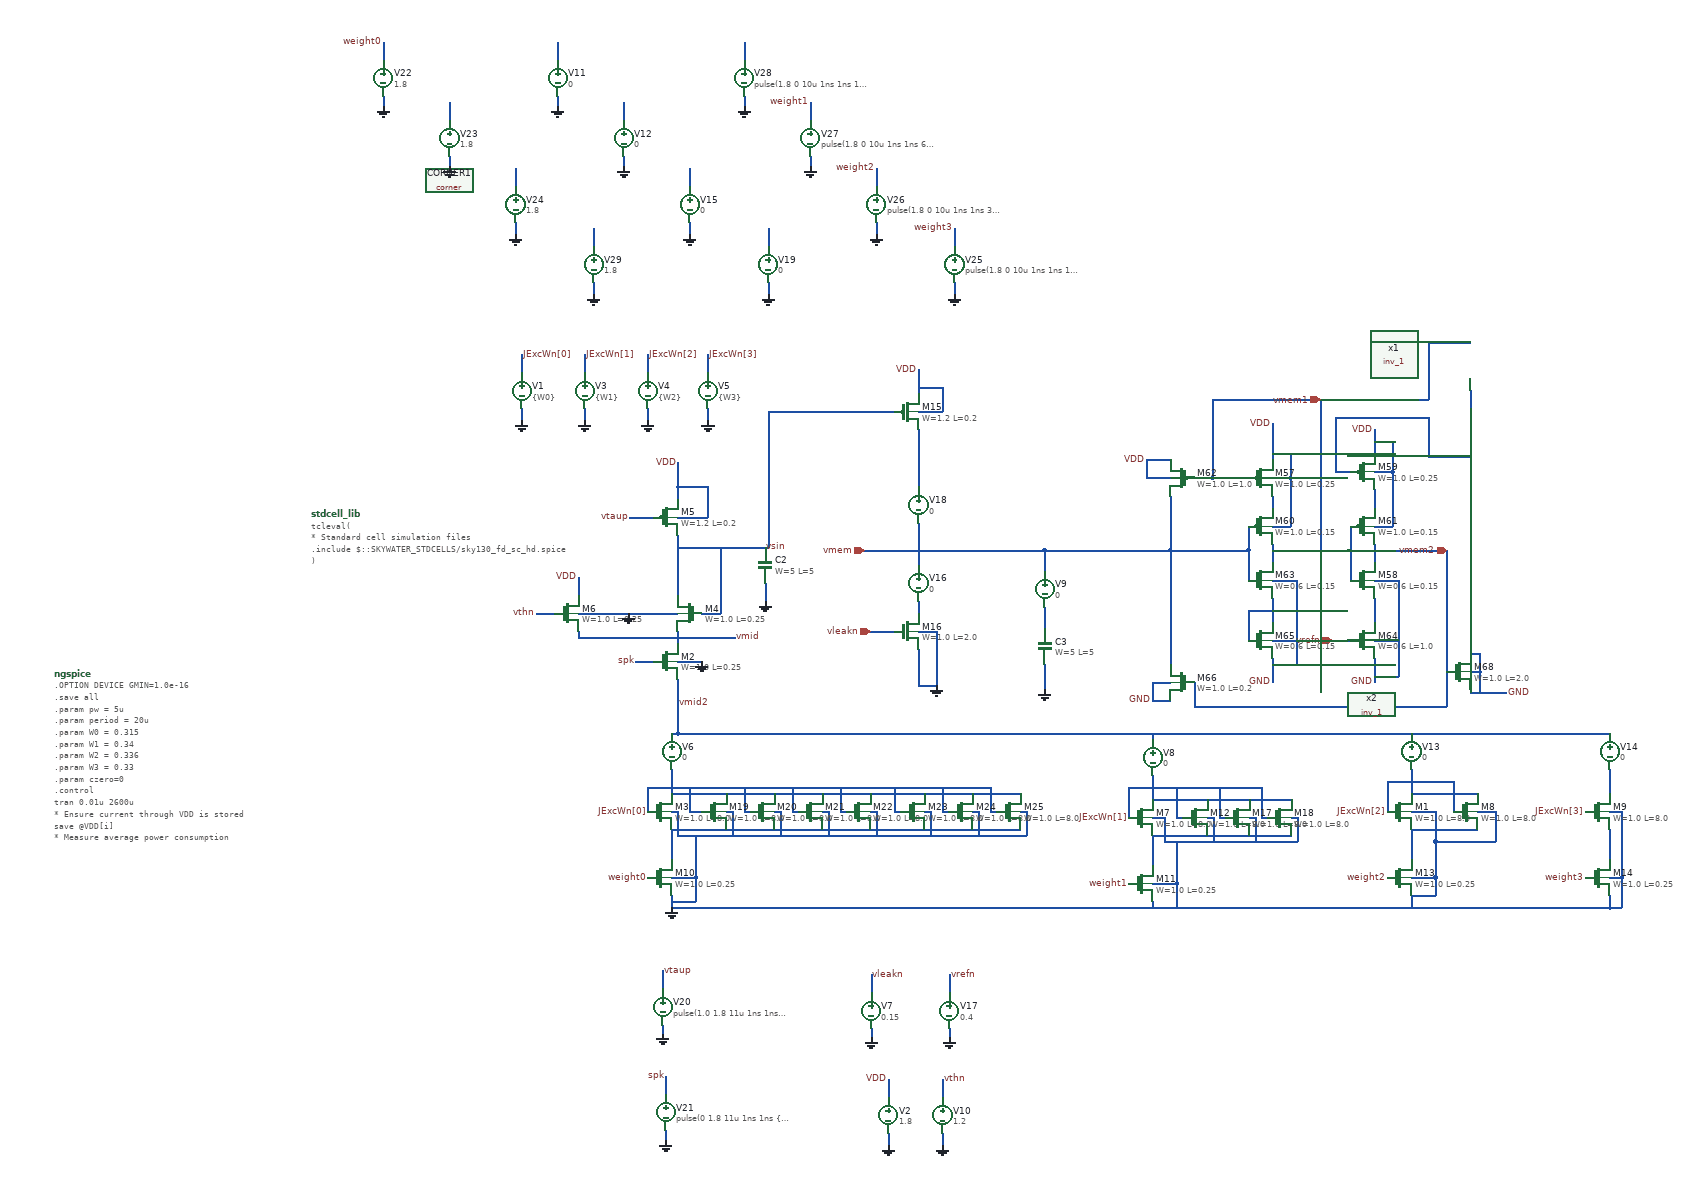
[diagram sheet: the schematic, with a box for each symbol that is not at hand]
v {xschem version=3.4.6RC file_version=1.2
}
G {}
K {}
V {}
S {}
E {}
N 690 335 690 355 {
lab=GND}
N 690 245 690 275 {
lab=VDD}
N 80 -870 80 -850 {
lab=GND}
N 80 -960 80 -930 {
lab=JExcWn[0]}
N 185 -870 185 -850 {
lab=GND}
N 185 -960 185 -930 {
lab=JExcWn[1]}
N 290 -870 290 -850 {
lab=GND}
N 290 -960 290 -930 {
lab=JExcWn[2]}
N 390 -870 390 -850 {
lab=GND}
N 390 -960 390 -930 {
lab=JExcWn[3]}
N 780 335 780 355 {
lab=GND}
N 780 245 780 275 {
lab=vthn}
N 315 65 315 95 {
lab=vtaup}
N 320 330 320 350 {
lab=GND}
N 320 240 320 270 {
lab=spk}
N 330 -260 330 -230 {
lab=#net1}
N 270 -450 300 -450 {
lab=spk}
N 340 -450 380 -450 {
lab=GND}
N 340 -620 340 -610 {
lab=vsin}
N 340 -660 340 -620 {
lab=vsin}
N 340 -780 340 -740 {
lab=VDD}
N 340 -740 340 -720 {
lab=VDD}
N 340 -690 390 -690 {
lab=VDD}
N 390 -740 390 -690 {
lab=VDD}
N 340 -740 390 -740 {
lab=VDD}
N 260 -690 300 -690 {
lab=vtaup}
N 340 -610 340 -560 {
lab=vsin}
N 340 -500 340 -480 {
lab=vmid}
N 380 -530 410 -530 {
lab=vsin}
N 410 -640 410 -530 {
lab=vsin}
N 175 -590 175 -560 {
lab=VDD}
N 105 -530 135 -530 {
lab=vthn}
N 210 -530 260 -530 {
lab=GND}
N 260 -530 290 -530 {
lab=GND}
N 290 -530 340 -530 {
lab=GND}
N 1130 -250 1130 -220 {
lab=#net2}
N 1890 -260 1890 -230 {
lab=#net3}
N 1560 -260 1560 -230 {
lab=#net4}
N 1130 -80 1170 -80 {
lab=GND}
N 1130 -40 1170 -40 {
lab=GND}
N 1170 -80 1170 -40 {
lab=GND}
N 1560 -60 1560 -40 {
lab=GND}
N 1560 -90 1600 -90 {
lab=GND}
N 1600 -150 1600 -90 {
lab=GND}
N 1600 -90 1600 -60 {
lab=GND}
N 1560 -60 1600 -60 {
lab=GND}
N 1890 -60 1890 -40 {
lab=GND}
N 485 -580 485 -550 {
lab=GND}
N 340 -640 485 -640 {
lab=vsin}
N 330 -60 330 -40 {
lab=GND}
N 330 -90 370 -90 {
lab=GND}
N 370 -90 370 -50 {
lab=GND}
N 330 -50 370 -50 {
lab=GND}
N 330 -170 330 -120 {
lab=#net5}
N 175 -500 175 -490 {
lab=vmid}
N 175 -490 340 -490 {
lab=vmid}
N 175 -530 210 -530 {
lab=GND}
N 340 -490 435 -490 {
lab=vmid}
N 340 -420 340 -330 {
lab=vmid2}
N 330 -330 340 -330 {
lab=vmid2}
N 330 -270 330 -260 {
lab=#net1}
N 1130 -260 1130 -250 {
lab=#net2}
N 1560 -270 1560 -260 {
lab=#net4}
N 1890 -270 1890 -260 {
lab=#net3}
N 1890 -200 1910 -200 {
lab=GND}
N 1910 -200 1910 -90 {
lab=GND}
N 1890 -90 1910 -90 {
lab=GND}
N 1910 -90 1910 -40 {
lab=GND}
N 1890 -40 1910 -40 {
lab=GND}
N 740 -935 740 -895 {
lab=VDD}
N 740 -865 780 -865 {
lab=VDD}
N 780 -905 780 -865 {
lab=VDD}
N 740 -905 780 -905 {
lab=VDD}
N 740 -500 770 -500 {
lab=GND}
N 770 -500 770 -450 {
lab=GND}
N 770 -450 770 -410 {
lab=GND}
N 740 -410 770 -410 {
lab=GND}
N 695 -635 885 -635 {
lab=vmem}
N 740 -470 740 -410 {
lab=GND}
N 740 -835 740 -740 {
lab=#net6}
N 950 -445 950 -400 {
lab=GND}
N 950 -635 950 -615 {
lab=vmem}
N 650 -635 695 -635 {
lab=vmem}
N 950 -615 950 -600 {
lab=vmem}
N 950 -540 950 -505 {
lab=#net7}
N 680 -865 700 -865 {
lab=vsin}
N 885 -635 950 -635 {
lab=vmem}
N 740 -680 740 -635 {
lab=vmem}
N 600 -865 680 -865 {
lab=vsin}
N 490 -865 490 -640 {
lab=vsin}
N 490 -865 600 -865 {
lab=vsin}
N 485 -640 490 -640 {
lab=vsin}
N 450 -1390 450 -1370 {
lab=GND}
N 450 -1480 450 -1450 {
lab=#net8}
N 560 -1290 560 -1270 {
lab=GND}
N 560 -1380 560 -1350 {
lab=weight1}
N 670 -1180 670 -1160 {
lab=GND}
N 670 -1270 670 -1240 {
lab=weight2}
N 800 -1080 800 -1060 {
lab=GND}
N 800 -1170 800 -1140 {
lab=weight3}
N 315 155 315 170 {lab=GND}
N 1560 -170 1560 -117.5 {lab=#net9}
N 1890 -170 1890 -120 {lab=#net10}
N 140 -1390 140 -1370 {
lab=GND}
N 140 -1480 140 -1450 {
lab=#net11}
N 250 -1290 250 -1270 {
lab=GND}
N 250 -1380 250 -1350 {
lab=#net12}
N 360 -1180 360 -1160 {
lab=GND}
N 360 -1270 360 -1240 {
lab=#net13}
N 490 -1080 490 -1060 {
lab=GND}
N 490 -1170 490 -1140 {
lab=#net14}
N 1328.75 -845 1328.75 -805 {
lab=VDD}
N 1328.75 -455 1328.75 -415 {
lab=GND}
N 1368.75 -555 1368.75 -445 {
lab=GND}
N 1328.75 -445 1368.75 -445 {
lab=GND}
N 1328.75 -485 1368.75 -485 {
lab=GND}
N 1328.75 -555 1328.75 -515 {
lab=#net15}
N 1288.75 -535 1288.75 -485 {
lab=#net15}
N 1288.75 -535 1328.75 -535 {
lab=#net15}
N 1328.75 -725 1328.75 -705 {
lab=#net16}
N 1328.75 -805 1328.75 -785 {
lab=VDD}
N 1328.75 -755 1358.75 -755 {
lab=VDD}
N 1358.75 -795 1358.75 -755 {
lab=VDD}
N 1328.75 -795 1358.75 -795 {
lab=VDD}
N 1358.75 -755 1358.75 -705 {
lab=VDD}
N 1228.75 -845 1228.75 -755 {
lab=vmem1}
N 1228.75 -755 1288.75 -755 {
lab=vmem1}
N 1158.75 -635 1288.75 -635 {
lab=vmem
.IC=0}
N 1498.75 -645 1498.75 -615 {
lab=vmem2}
N 1458.75 -675 1458.75 -585 {
lab=vmem1}
N 1498.75 -675 1528.75 -675 {
lab=VDD}
N 1528.75 -705 1528.75 -675 {
lab=VDD}
N 1498.75 -585 1538.75 -585 {
lab=GND}
N 1538.75 -585 1538.75 -555 {
lab=GND}
N 1328.75 -635 1458.75 -635 {
lab=vmem1}
N 1498.75 -555 1498.75 -515 {
lab=#net17}
N 1538.75 -555 1538.75 -425 {
lab=GND}
N 1498.75 -455 1498.75 -415 {
lab=GND}
N 1498.75 -425 1538.75 -425 {
lab=GND}
N 1498.75 -735 1498.75 -705 {
lab=#net18}
N 1498.75 -765 1528.75 -765 {
lab=VDD}
N 1528.75 -765 1528.75 -705 {
lab=VDD}
N 1528.75 -815 1528.75 -765 {
lab=VDD}
N 1498.75 -815 1528.75 -815 {
lab=VDD}
N 1498.75 -835 1498.75 -795 {
lab=VDD}
N 1433.75 -855 1433.75 -765 {
lab=#net19}
N 1678.75 -397.5 1718.75 -397.5 {
lab=GND}
N 1048.75 -635 1158.75 -635 {
lab=vmem
.IC=0}
N 1408.75 -885 1408.75 -635 {
lab=vmem1}
N 1228.75 -885 1408.75 -885 {
lab=vmem1}
N 1228.75 -885 1228.75 -845 {
lab=vmem1}
N 1498.75 -485 1538.75 -485 {
lab=GND}
N 1198.75 -415 1198.75 -375 {
lab=vmem2}
N 1128.75 -385 1158.75 -385 {
lab=GND}
N 1128.75 -415 1158.75 -415 {
lab=GND}
N 1128.75 -415 1128.75 -385 {
lab=GND}
N 1158.75 -495 1158.75 -445 {
lab=vmem}
N 1618.75 -635 1618.75 -375 {
lab=vmem2}
N 1158.75 -635 1158.75 -495 {
lab=vmem}
N 1218.75 -375 1268.75 -375 {
lab=vmem2}
N 1268.75 -375 1598.75 -375 {
lab=vmem2}
N 1438.75 -485 1458.75 -485 {
lab=vrefn}
N 1428.75 -485 1438.75 -485 {
lab=vrefn}
N 1198.75 -755 1228.75 -755 {
lab=vmem1}
N 1118.75 -755 1158.75 -755 {
lab=VDD}
N 1118.75 -785 1118.75 -755 {
lab=VDD}
N 1118.75 -785 1158.75 -785 {
lab=VDD}
N 1158.75 -725 1158.75 -635 {
lab=vmem}
N 1288.75 -675 1288.75 -635 {
lab=vmem}
N 1288.75 -635 1288.75 -585 {
lab=vmem}
N 1328.75 -645 1328.75 -615 {
lab=vmem1}
N 1328.75 -585 1368.75 -585 {
lab=GND}
N 1368.75 -585 1368.75 -555 {
lab=GND}
N 1358.75 -705 1358.75 -675 {
lab=VDD}
N 1328.75 -675 1358.75 -675 {
lab=VDD}
N 1658.75 -402.5 1658.75 -397.5 {
lab=GND}
N 1658.75 -397.5 1678.75 -397.5 {
lab=GND}
N 1673.75 -432.5 1673.75 -397.5 {
lab=GND}
N 1658.75 -432.5 1673.75 -432.5 {
lab=GND}
N 1658.75 -462.5 1673.75 -462.5 {
lab=GND}
N 1673.75 -462.5 1673.75 -432.5 {
lab=GND}
N 1198.75 -375 1218.75 -375 {
lab=vmem2}
N 1498.75 -635 1618.75 -635 {
lab=vmem2}
N 1598.75 -375 1618.75 -375 {
lab=vmem2}
N 1433.75 -765 1458.75 -765 {
lab=#net19}
N 1658.75 -900 1658.75 -870 {
lab=#net20}
N 1588.75 -855 1588.75 -790 {lab=#net19}
N 1588.75 -980 1588.75 -885 {lab=vmem1}
N 1588.75 -980 1658.75 -980 {lab=vmem1}
N 1588.75 -790 1658.75 -790 {lab=#net19}
N 1433.75 -855 1588.75 -855 {lab=#net19}
N 1403.75 -885 1588.75 -885 {lab=vmem1}
N 1158.75 -755 1161.25 -755 {lab=VDD}
N 660 -500 700 -500 {lab=vleakn}
N 661.25 71.25 661.25 101.25 {
lab=vleakn}
N 661.25 161.25 661.25 176.25 {lab=GND}
N 950 -635 1048.75 -635 {lab=vmem}
N 740 -550 740 -530 {lab=#net21}
N 740 -635 740 -610 {lab=vmem}
N 791.25 71.25 791.25 101.25 {
lab=vrefn}
N 791.25 161.25 791.25 176.25 {lab=GND}
N 1560 -170 1670 -170 {lab=#net9}
N 1560 -230 1670 -230 {lab=#net4}
N 1560 -200 1600 -200 {lab=GND}
N 1600 -200 1600 -150 {lab=GND}
N 1670 -200 1700 -200 {lab=GND}
N 1700 -200 1700 -150 {lab=GND}
N 1600 -150 1700 -150 {lab=GND}
N 1630 -250 1630 -200 {lab=JExcWn[2]}
N 1520 -250 1520 -200 {lab=JExcWn[2]}
N 1520 -250 1630 -250 {lab=JExcWn[2]}
N 1130 -220 1360 -220 {lab=#net2}
N 1130 -160 1360 -160 {lab=#net22}
N 1130 -190 1150 -190 {lab=GND}
N 1150 -190 1150 -150 {lab=GND}
N 1220 -190 1230 -190 {lab=GND}
N 1230 -190 1230 -150 {lab=GND}
N 1290 -190 1300 -190 {lab=GND}
N 1300 -190 1300 -150 {lab=GND}
N 1360 -190 1370 -190 {lab=GND}
N 1370 -190 1370 -150 {lab=GND}
N 1150 -150 1370 -150 {lab=GND}
N 1170 -150 1170 -80 {lab=GND}
N 1170 -190 1180 -190 {lab=JExcWn[1]}
N 1170 -240 1170 -190 {lab=JExcWn[1]}
N 1240 -190 1250 -190 {lab=JExcWn[1]}
N 1240 -240 1240 -190 {lab=JExcWn[1]}
N 1310 -190 1320 -190 {lab=JExcWn[1]}
N 1310 -240 1310 -190 {lab=JExcWn[1]}
N 1090 -240 1310 -240 {lab=JExcWn[1]}
N 1090 -240 1090 -190 {lab=JExcWn[1]}
N 330 -230 910 -230 {lab=#net1}
N 330 -170 910 -170 {lab=#net5}
N 330 -200 340 -200 {lab=GND}
N 340 -200 340 -160 {lab=GND}
N 420 -200 430 -200 {lab=GND}
N 430 -200 430 -160 {lab=GND}
N 500 -200 510 -200 {lab=GND}
N 510 -200 510 -160 {lab=GND}
N 580 -200 590 -200 {lab=GND}
N 590 -200 590 -160 {lab=GND}
N 660 -200 670 -200 {lab=GND}
N 670 -200 670 -160 {lab=GND}
N 750 -200 760 -200 {lab=GND}
N 760 -200 760 -160 {lab=GND}
N 830 -200 840 -200 {lab=GND}
N 840 -200 840 -160 {lab=GND}
N 910 -200 920 -200 {lab=GND}
N 920 -200 920 -160 {lab=GND}
N 340 -160 920 -160 {lab=GND}
N 370 -160 370 -90 {lab=GND}
N 360 -200 380 -200 {lab=JExcWn[0]}
N 360 -240 360 -200 {lab=JExcWn[0]}
N 450 -200 460 -200 {lab=JExcWn[0]}
N 450 -240 450 -200 {lab=JExcWn[0]}
N 530 -200 540 -200 {lab=JExcWn[0]}
N 530 -240 530 -200 {lab=JExcWn[0]}
N 610 -200 620 -200 {lab=JExcWn[0]}
N 610 -240 610 -200 {lab=JExcWn[0]}
N 700 -200 710 -200 {lab=JExcWn[0]}
N 700 -240 700 -200 {lab=JExcWn[0]}
N 780 -200 790 -200 {lab=JExcWn[0]}
N 780 -240 780 -200 {lab=JExcWn[0]}
N 860 -200 870 -200 {lab=JExcWn[0]}
N 860 -240 860 -200 {lab=JExcWn[0]}
N 290 -240 860 -240 {lab=JExcWn[0]}
N 290 -240 290 -200 {lab=JExcWn[0]}
N 340 -330 1890 -330 {lab=vmid2}
N 330 -40 1890 -40 {lab=GND}
N 1130 -50 1130 -40 {lab=GND}
N 1130 -330 1130 -320 {lab=vmid2}
N 1130 -160 1130 -110 {lab=#net22}
N -150 -1390 -150 -1370 {
lab=GND}
N -150 -1480 -150 -1450 {
lab=weight0}
N -40 -1290 -40 -1270 {
lab=GND}
N -40 -1380 -40 -1350 {
lab=#net23}
N 70 -1180 70 -1160 {
lab=GND}
N 70 -1270 70 -1240 {
lab=#net24}
N 200 -1080 200 -1060 {
lab=GND}
N 200 -1170 200 -1140 {
lab=#net25}
C {devices/vsource.sym} 690 305 0 0 {name=V2 value=1.8
}
C {devices/lab_pin.sym} 690 245 0 0 {name=p35 sig_type=std_logic lab=VDD}
C {devices/code.sym} -270 -695 0 0 {name=stdcell_lib only_toplevel=true value="tcleval(
* Standard cell simulation files
.include $::SKYWATER_STDCELLS/sky130_fd_sc_hd.spice
)"}
C {sky130_fd_pr/corner.sym} -390 -695 0 0 {name=CORNER1 only_toplevel=true corner=tt}
C {devices/vsource.sym} 80 -900 0 0 {name=V1 value=\{W0\}
}
C {devices/vsource.sym} 185 -900 0 0 {name=V3 value=\{W1\}
}
C {devices/vsource.sym} 290 -900 0 0 {name=V4 value=\{W2\}
}
C {devices/vsource.sym} 390 -900 0 0 {name=V5 value=\{W3\}
}
C {devices/lab_pin.sym} 80 -960 2 0 {name=p27 sig_type=std_logic lab=JExcWn[0]}
C {devices/lab_pin.sym} 185 -960 2 0 {name=p28 sig_type=std_logic lab=JExcWn[1]}
C {devices/lab_pin.sym} 290 -960 2 0 {name=p29 sig_type=std_logic lab=JExcWn[2]}
C {devices/lab_pin.sym} 390 -960 2 0 {name=p30 sig_type=std_logic lab=JExcWn[3]}
C {devices/vsource.sym} 780 305 0 0 {name=V10 value=1.2
}
C {devices/lab_pin.sym} 780 245 2 0 {name=p34 sig_type=std_logic lab=vthn}
C {devices/lab_pin.sym} 315 65 2 0 {name=p60 sig_type=std_logic lab=vtaup}
C {devices/vsource.sym} 315 125 0 0 {name=V20 value="pulse(1.0 1.8 11u 1ns 1ns \{pw\} \{period\} 200)"}
C {devices/lab_pin.sym} 320 240 2 1 {name=p63 sig_type=std_logic lab=spk}
C {devices/vsource.sym} 320 300 0 0 {name=V21 value="pulse(0 1.8 11u 1ns 1ns \{pw\} \{period\} 200)"}
C {sky130_fd_pr/nfet_01v8.sym} 320 -450 0 0 {name=M2
L=0.25
W=1.0
nf=1 
mult=1
ad="'int((nf+1)/2) * W/nf * 0.29'" 
pd="'2*int((nf+1)/2) * (W/nf + 0.29)'"
as="'int((nf+2)/2) * W/nf * 0.29'" 
ps="'2*int((nf+2)/2) * (W/nf + 0.29)'"
nrd="'0.29 / W'" nrs="'0.29 / W'"
sa=0 sb=0 sd=0
model=nfet_01v8
spiceprefix=X
}
C {sky130_fd_pr/pfet_01v8.sym} 320 -690 0 0 {name=M5
L=0.2
W=1.2
nf=1
mult=1
ad="'int((nf+1)/2) * W/nf * 0.29'" 
pd="'2*int((nf+1)/2) * (W/nf + 0.29)'"
as="'int((nf+2)/2) * W/nf * 0.29'" 
ps="'2*int((nf+2)/2) * (W/nf + 0.29)'"
nrd="'0.29 / W'" nrs="'0.29 / W'"
sa=0 sb=0 sd=0
model=pfet_01v8
spiceprefix=X
}
C {devices/lab_pin.sym} 340 -780 0 0 {name=p32 sig_type=std_logic lab=VDD}
C {sky130_fd_pr/nfet_01v8.sym} 360 -530 0 1 {name=M4
L=0.25
W=1.0
nf=1 
mult=1
ad="'int((nf+1)/2) * W/nf * 0.29'" 
pd="'2*int((nf+1)/2) * (W/nf + 0.29)'"
as="'int((nf+2)/2) * W/nf * 0.29'" 
ps="'2*int((nf+2)/2) * (W/nf + 0.29)'"
nrd="'0.29 / W'" nrs="'0.29 / W'"
sa=0 sb=0 sd=0
model=nfet_01v8
spiceprefix=X
}
C {sky130_fd_pr/nfet_01v8.sym} 155 -530 0 0 {name=M6
L=0.25
W=1.0
nf=1 
mult=1
ad="'int((nf+1)/2) * W/nf * 0.29'" 
pd="'2*int((nf+1)/2) * (W/nf + 0.29)'"
as="'int((nf+2)/2) * W/nf * 0.29'" 
ps="'2*int((nf+2)/2) * (W/nf + 0.29)'"
nrd="'0.29 / W'" nrs="'0.29 / W'"
sa=0 sb=0 sd=0
model=nfet_01v8
spiceprefix=X
}
C {devices/lab_pin.sym} 175 -590 0 0 {name=p56 sig_type=std_logic lab=VDD}
C {sky130_fd_pr/nfet_01v8.sym} 1870 -200 0 0 {name=M9
L=8.0
W=1.0
nf=1
mult=1
ad="'int((nf+1)/2) * W/nf * 0.29'" 
pd="'2*int((nf+1)/2) * (W/nf + 0.29)'"
as="'int((nf+2)/2) * W/nf * 0.29'" 
ps="'2*int((nf+2)/2) * (W/nf + 0.29)'"
nrd="'0.29 / W'" nrs="'0.29 / W'"
sa=0 sb=0 sd=0
model=nfet_01v8
spiceprefix=X
}
C {sky130_fd_pr/nfet_01v8.sym} 310 -90 0 0 {name=M10
L=0.25
W=1.0
nf=1
mult=1
ad="'int((nf+1)/2) * W/nf * 0.29'" 
pd="'2*int((nf+1)/2) * (W/nf + 0.29)'"
as="'int((nf+2)/2) * W/nf * 0.29'" 
ps="'2*int((nf+2)/2) * (W/nf + 0.29)'"
nrd="'0.29 / W'" nrs="'0.29 / W'"
sa=0 sb=0 sd=0
model=nfet_01v8
spiceprefix=X
}
C {sky130_fd_pr/nfet_01v8.sym} 1110 -80 0 0 {name=M11
L=0.25
W=1.0
nf=1 
mult=1
ad="'int((nf+1)/2) * W/nf * 0.29'" 
pd="'2*int((nf+1)/2) * (W/nf + 0.29)'"
as="'int((nf+2)/2) * W/nf * 0.29'" 
ps="'2*int((nf+2)/2) * (W/nf + 0.29)'"
nrd="'0.29 / W'" nrs="'0.29 / W'"
sa=0 sb=0 sd=0
model=nfet_01v8
spiceprefix=X
}
C {sky130_fd_pr/nfet_01v8.sym} 1540 -90 0 0 {name=M13
L=0.25
W=1.0
nf=1 
mult=1
ad="'int((nf+1)/2) * W/nf * 0.29'" 
pd="'2*int((nf+1)/2) * (W/nf + 0.29)'"
as="'int((nf+2)/2) * W/nf * 0.29'" 
ps="'2*int((nf+2)/2) * (W/nf + 0.29)'"
nrd="'0.29 / W'" nrs="'0.29 / W'"
sa=0 sb=0 sd=0
model=nfet_01v8
spiceprefix=X
}
C {sky130_fd_pr/nfet_01v8.sym} 1870 -90 0 0 {name=M14
L=0.25
W=1.0
nf=1 
mult=1
ad="'int((nf+1)/2) * W/nf * 0.29'" 
pd="'2*int((nf+1)/2) * (W/nf + 0.29)'"
as="'int((nf+2)/2) * W/nf * 0.29'" 
ps="'2*int((nf+2)/2) * (W/nf + 0.29)'"
nrd="'0.29 / W'" nrs="'0.29 / W'"
sa=0 sb=0 sd=0
model=nfet_01v8
spiceprefix=X
}
C {devices/lab_pin.sym} 1090 -80 0 0 {name=p67 lab=weight1

}
C {devices/lab_pin.sym} 1520 -90 0 0 {name=p68 lab=weight2

}
C {devices/lab_pin.sym} 1850 -90 0 0 {name=p69 lab=weight3

}
C {devices/lab_pin.sym} 290 -90 0 0 {name=p70 lab=weight0

}
C {devices/lab_pin.sym} 290 -200 0 0 {name=p72 lab=JExcWn[0]

}
C {devices/lab_pin.sym} 1090 -190 0 0 {name=p73 lab=JExcWn[1]

}
C {devices/lab_pin.sym} 1520 -200 0 0 {name=p74 lab=JExcWn[2]

}
C {devices/lab_pin.sym} 1850 -200 0 0 {name=p75 lab=JExcWn[3]

}
C {sky130_fd_pr/cap_mim_m3_1.sym} 485 -610 0 0 {name=C2 model=cap_mim_m3_1 W=5 L=5 MF=1 spiceprefix=X}
C {devices/vsource.sym} 330 -300 0 0 {name=V6 value=0
}
C {devices/vsource.sym} 1130 -290 0 0 {name=V8 value=0
}
C {devices/vsource.sym} 1560 -300 0 0 {name=V13 value=0
}
C {devices/vsource.sym} 1890 -300 0 0 {name=V14 value=0
}
C {devices/lab_pin.sym} 105 -530 0 0 {name=p1 lab=vthn

}
C {devices/lab_pin.sym} 270 -450 0 0 {name=p2 lab=spk

}
C {devices/lab_pin.sym} 435 -490 2 0 {name=p3 sig_type=std_logic lab=vmid}
C {devices/lab_pin.sym} 485 -640 2 0 {name=p4 sig_type=std_logic lab=vsin}
C {devices/lab_pin.sym} 260 -690 0 0 {name=p5 lab=vtaup

}
C {devices/lab_pin.sym} 340 -380 2 0 {name=p6 sig_type=std_logic lab=vmid2}
C {sky130_fd_pr/cap_mim_m3_1.sym} 950 -475 2 0 {name=C3 model=cap_mim_m3_1 W=5 L=5 MF=1 spiceprefix=X}
C {devices/ipin.sym} 660 -500 0 0 {name=p7 lab=vleakn
}
C {sky130_fd_pr/pfet_01v8.sym} 720 -865 0 0 {name=M15
L=0.2
W=1.2
nf=1
mult=1
ad="'int((nf+1)/2) * W/nf * 0.29'" 
pd="'2*int((nf+1)/2) * (W/nf + 0.29)'"
as="'int((nf+2)/2) * W/nf * 0.29'" 
ps="'2*int((nf+2)/2) * (W/nf + 0.29)'"
nrd="'0.29 / W'" nrs="'0.29 / W'"
sa=0 sb=0 sd=0
model=pfet_01v8
spiceprefix=X
}
C {devices/iopin.sym} 650 -635 3 0 {name=p9 lab=vmem
}
C {sky130_fd_pr/nfet_01v8.sym} 720 -500 0 0 {name=M16
L=2.0
W=1.0
nf=1 
mult=1
ad="'int((nf+1)/2) * W/nf * 0.29'" 
pd="'2*int((nf+1)/2) * (W/nf + 0.29)'"
as="'int((nf+2)/2) * W/nf * 0.29'" 
ps="'2*int((nf+2)/2) * (W/nf + 0.29)'"
nrd="'0.29 / W'" nrs="'0.29 / W'"
sa=0 sb=0 sd=0
model=nfet_01v8
spiceprefix=X
}
C {devices/vsource.sym} 740 -710 0 0 {name=V18 value=0
}
C {devices/lab_pin.sym} 740 -935 0 0 {name=p11 sig_type=std_logic lab=VDD}
C {devices/code_shown.sym} -697.6171875 -429.6484375 0 0 {name=ngspice only_toplevel=false value="
.OPTION DEVICE GMIN=1.0e-16

.save all
.param pw = 5u
.param period = 20u

.param W0 = 0.315
.param W1 = 0.34
.param W2 = 0.336
.param W3 = 0.33
.param czero=0

.control
tran 0.01u 2600u

* Ensure current through VDD is stored
save @VDD[i]  

* Measure average power consumption
meas tran Power_VDD AVG (v(VDD) * @VDD[i])

* Print power value for debugging
print Power_VDD

* Save results
write 'synapse_weight_new.raw' vmem vsin weight1 weight2 weight3 weight0 spk Power_VDD

* Plot signals
plot vmem vsin

* Plot instantaneous power over time
plot (V(VDD) * i(V2))
.endc

"}
C {devices/vsource.sym} 800 -1110 0 0 {name=V25 value="pulse(1.8 0 10u 1ns 1ns 160us 320us 8)"}
C {devices/vsource.sym} 670 -1210 0 0 {name=V26 value="pulse(1.8 0 10u 1ns 1ns 320us 640us 4)"}
C {devices/vsource.sym} 560 -1320 0 0 {name=V27 value="pulse(1.8 0 10u 1ns 1ns 640us 1280us 2)"}
C {devices/vsource.sym} 450 -1420 0 0 {name=V28 value="pulse(1.8 0 10u 1ns 1ns 1280us 2560us 1)"}
C {devices/gnd.sym} 380 -450 0 0 {name=l2 lab=GND}
C {devices/gnd.sym} 485 -550 0 0 {name=l3 lab=GND}
C {devices/gnd.sym} 330 -40 0 0 {name=l1 lab=GND}
C {devices/gnd.sym} 770 -410 0 0 {name=l4 lab=GND}
C {devices/gnd.sym} 950 -402.5 0 0 {name=l5 lab=GND}
C {devices/gnd.sym} 257.5 -530 2 0 {name=l6 lab=GND}
C {devices/gnd.sym} 80 -850 0 0 {name=l8 lab=GND}
C {devices/gnd.sym} 185 -850 0 0 {name=l9 lab=GND}
C {devices/gnd.sym} 290 -850 0 0 {name=l10 lab=GND}
C {devices/gnd.sym} 390 -850 0 0 {name=l11 lab=GND}
C {devices/gnd.sym} 450 -1372.5 0 0 {name=l7 lab=GND}
C {devices/gnd.sym} 560 -1272.5 0 0 {name=l12 lab=GND}
C {devices/gnd.sym} 670 -1160 0 0 {name=l13 lab=GND}
C {devices/gnd.sym} 800 -1060 0 0 {name=l14 lab=GND}
C {devices/gnd.sym} 315 170 0 0 {name=l15 lab=GND}
C {devices/gnd.sym} 320 347.5 0 0 {name=l16 lab=GND}
C {devices/gnd.sym} 690 355 0 0 {name=l17 lab=GND}
C {devices/gnd.sym} 780 355 0 0 {name=l18 lab=GND}
C {devices/lab_pin.sym} 560 -1380 0 0 {name=p10 sig_type=std_logic lab=weight1}
C {devices/lab_pin.sym} 670 -1270 0 0 {name=p12 sig_type=std_logic lab=weight2}
C {devices/lab_pin.sym} 800 -1170 0 0 {name=p13 sig_type=std_logic lab=weight3}
C {devices/gnd.sym} 140 -1372.5 0 0 {name=l20 lab=GND}
C {devices/gnd.sym} 250 -1272.5 0 0 {name=l21 lab=GND}
C {devices/gnd.sym} 360 -1160 0 0 {name=l26 lab=GND}
C {devices/gnd.sym} 490 -1060 0 0 {name=l27 lab=GND}
C {devices/vsource.sym} 140 -1420 0 0 {name=V11 value=0
}
C {devices/vsource.sym} 250 -1320 0 0 {name=V12 value=0
}
C {devices/vsource.sym} 360 -1210 0 0 {name=V15 value=0
}
C {devices/vsource.sym} 490 -1110 0 0 {name=V19 value=0
}
C {devices/lab_pin.sym} 1328.75 -845 0 0 {name=p112 sig_type=std_logic lab=VDD}
C {devices/lab_pin.sym} 1328.75 -415 0 0 {name=p113 sig_type=std_logic lab=GND}
C {devices/lab_pin.sym} 1498.75 -415 0 0 {name=p122 sig_type=std_logic lab=GND}
C {devices/lab_pin.sym} 1498.75 -835 0 0 {name=p123 sig_type=std_logic lab=VDD}
C {devices/lab_pin.sym} 1718.75 -397.5 2 0 {name=p124 sig_type=std_logic lab=GND}
C {devices/lab_pin.sym} 1128.75 -385 2 1 {name=p125 sig_type=std_logic lab=GND}
C {devices/ipin.sym} 1428.75 -485 1 0 {name=p127 lab=vrefn
}
C {sky130_fd_pr/pfet_01v8.sym} 1308.75 -755 0 0 {name=M57
L=0.25
W=1.0
nf=1
mult=1
ad="'int((nf+1)/2) * W/nf * 0.29'" 
pd="'2*int((nf+1)/2) * (W/nf + 0.29)'"
as="'int((nf+2)/2) * W/nf * 0.29'" 
ps="'2*int((nf+2)/2) * (W/nf + 0.29)'"
nrd="'0.29 / W'" nrs="'0.29 / W'"
sa=0 sb=0 sd=0
model=pfet_01v8
spiceprefix=X
}
C {sky130_fd_pr/nfet_01v8.sym} 1478.75 -585 0 0 {name=M58
L=0.15
W=0.6
nf=1 
mult=1
ad="'int((nf+1)/2) * W/nf * 0.29'" 
pd="'2*int((nf+1)/2) * (W/nf + 0.29)'"
as="'int((nf+2)/2) * W/nf * 0.29'" 
ps="'2*int((nf+2)/2) * (W/nf + 0.29)'"
nrd="'0.29 / W'" nrs="'0.29 / W'"
sa=0 sb=0 sd=0
model=nfet_01v8
spiceprefix=X
}
C {devices/lab_pin.sym} 1118.75 -785 0 0 {name=p130 sig_type=std_logic lab=VDD}
C {sky130_fd_pr/pfet_01v8.sym} 1478.75 -765 0 0 {name=M59
L=0.25
W=1.0
nf=1
mult=1
ad="'int((nf+1)/2) * W/nf * 0.29'" 
pd="'2*int((nf+1)/2) * (W/nf + 0.29)'"
as="'int((nf+2)/2) * W/nf * 0.29'" 
ps="'2*int((nf+2)/2) * (W/nf + 0.29)'"
nrd="'0.29 / W'" nrs="'0.29 / W'"
sa=0 sb=0 sd=0
model=pfet_01v8
spiceprefix=X
}
C {sky130_fd_pr/pfet_01v8.sym} 1308.75 -675 0 0 {name=M60
L=0.15
W=1.0
nf=1
mult=1
ad="'int((nf+1)/2) * W/nf * 0.29'" 
pd="'2*int((nf+1)/2) * (W/nf + 0.29)'"
as="'int((nf+2)/2) * W/nf * 0.29'" 
ps="'2*int((nf+2)/2) * (W/nf + 0.29)'"
nrd="'0.29 / W'" nrs="'0.29 / W'"
sa=0 sb=0 sd=0
model=pfet_01v8
spiceprefix=X
}
C {sky130_fd_pr/pfet_01v8.sym} 1478.75 -675 0 0 {name=M61
L=0.15
W=1.0
nf=1
mult=1
ad="'int((nf+1)/2) * W/nf * 0.29'" 
pd="'2*int((nf+1)/2) * (W/nf + 0.29)'"
as="'int((nf+2)/2) * W/nf * 0.29'" 
ps="'2*int((nf+2)/2) * (W/nf + 0.29)'"
nrd="'0.29 / W'" nrs="'0.29 / W'"
sa=0 sb=0 sd=0
model=pfet_01v8
spiceprefix=X
}
C {sky130_fd_pr/pfet_01v8.sym} 1178.75 -755 0 1 {name=M62
L=1.0
W=1.0
nf=1
mult=1
ad="'int((nf+1)/2) * W/nf * 0.29'" 
pd="'2*int((nf+1)/2) * (W/nf + 0.29)'"
as="'int((nf+2)/2) * W/nf * 0.29'" 
ps="'2*int((nf+2)/2) * (W/nf + 0.29)'"
nrd="'0.29 / W'" nrs="'0.29 / W'"
sa=0 sb=0 sd=0
model=pfet_01v8
spiceprefix=X
}
C {sky130_fd_pr/nfet_01v8.sym} 1308.75 -585 0 0 {name=M63
L=0.15
W=0.6
nf=1 
mult=1
ad="'int((nf+1)/2) * W/nf * 0.29'" 
pd="'2*int((nf+1)/2) * (W/nf + 0.29)'"
as="'int((nf+2)/2) * W/nf * 0.29'" 
ps="'2*int((nf+2)/2) * (W/nf + 0.29)'"
nrd="'0.29 / W'" nrs="'0.29 / W'"
sa=0 sb=0 sd=0
model=nfet_01v8
spiceprefix=X
}
C {sky130_fd_pr/nfet_01v8.sym} 1478.75 -485 0 0 {name=M64
L=1.0
W=0.6
nf=1 
mult=1
ad="'int((nf+1)/2) * W/nf * 0.29'" 
pd="'2*int((nf+1)/2) * (W/nf + 0.29)'"
as="'int((nf+2)/2) * W/nf * 0.29'" 
ps="'2*int((nf+2)/2) * (W/nf + 0.29)'"
nrd="'0.29 / W'" nrs="'0.29 / W'"
sa=0 sb=0 sd=0
model=nfet_01v8
spiceprefix=X
}
C {sky130_fd_pr/nfet_01v8.sym} 1308.75 -485 0 0 {name=M65
L=0.15
W=0.6
nf=1 
mult=1
ad="'int((nf+1)/2) * W/nf * 0.29'" 
pd="'2*int((nf+1)/2) * (W/nf + 0.29)'"
as="'int((nf+2)/2) * W/nf * 0.29'" 
ps="'2*int((nf+2)/2) * (W/nf + 0.29)'"
nrd="'0.29 / W'" nrs="'0.29 / W'"
sa=0 sb=0 sd=0
model=nfet_01v8
spiceprefix=X
}
C {sky130_fd_pr/nfet_01v8.sym} 1178.75 -415 0 1 {name=M66
L=0.2
W=1.0
nf=1 
mult=1
ad="'int((nf+1)/2) * W/nf * 0.29'" 
pd="'2*int((nf+1)/2) * (W/nf + 0.29)'"
as="'int((nf+2)/2) * W/nf * 0.29'" 
ps="'2*int((nf+2)/2) * (W/nf + 0.29)'"
nrd="'0.29 / W'" nrs="'0.29 / W'"
sa=0 sb=0 sd=0
model=nfet_01v8
spiceprefix=X
}
C {sky130_fd_pr/nfet_01v8.sym} 1638.75 -432.5 0 0 {name=M68
L=2.0
W=1.0
nf=1 
mult=1
ad="'int((nf+1)/2) * W/nf * 0.29'" 
pd="'2*int((nf+1)/2) * (W/nf + 0.29)'"
as="'int((nf+2)/2) * W/nf * 0.29'" 
ps="'2*int((nf+2)/2) * (W/nf + 0.29)'"
nrd="'0.29 / W'" nrs="'0.29 / W'"
sa=0 sb=0 sd=0
model=nfet_01v8
spiceprefix=X
}
C {sky130_stdcells/inv_1.sym} 1658.75 -940 3 1 {name=x1 VGND=0 VNB=0 VPB=VDD VPWR=VDD prefix=sky130_fd_sc_hd__ }
C {sky130_stdcells/inv_1.sym} 1658.75 -830 3 1 {name=x2 VGND=0 VNB=0 VPB=VDD VPWR=VDD prefix=sky130_fd_sc_hd__ }
C {devices/iopin.sym} 1408.75 -885 3 0 {name=p133 lab=vmem1
}
C {devices/iopin.sym} 1618.75 -635 0 0 {name=p134 lab=vmem2
}
C {devices/lab_pin.sym} 661.25 71.25 2 0 {name=p14 sig_type=std_logic lab=vleakn}
C {devices/vsource.sym} 661.25 131.25 0 0 {name=V7 value=0.15}
C {devices/gnd.sym} 661.25 176.25 0 0 {name=l19 lab=GND}
C {devices/vsource.sym} 950 -570 0 0 {name=V9 value=0
}
C {devices/vsource.sym} 740 -580 0 0 {name=V16 value=0
}
C {devices/lab_pin.sym} 791.25 71.25 2 0 {name=p15 sig_type=std_logic lab=vrefn}
C {devices/vsource.sym} 791.25 131.25 0 0 {name=V17 value=0.4}
C {devices/gnd.sym} 791.25 176.25 0 0 {name=l22 lab=GND}
C {sky130_fd_pr/nfet_01v8.sym} 1540 -200 0 0 {name=M1
L=8.0
W=1.0
nf=1
mult=1
ad="'int((nf+1)/2) * W/nf * 0.29'" 
pd="'2*int((nf+1)/2) * (W/nf + 0.29)'"
as="'int((nf+2)/2) * W/nf * 0.29'" 
ps="'2*int((nf+2)/2) * (W/nf + 0.29)'"
nrd="'0.29 / W'" nrs="'0.29 / W'"
sa=0 sb=0 sd=0
model=nfet_01v8
spiceprefix=X
}
C {sky130_fd_pr/nfet_01v8.sym} 1650 -200 0 0 {name=M8
L=8.0
W=1.0
nf=1
mult=1
ad="'int((nf+1)/2) * W/nf * 0.29'" 
pd="'2*int((nf+1)/2) * (W/nf + 0.29)'"
as="'int((nf+2)/2) * W/nf * 0.29'" 
ps="'2*int((nf+2)/2) * (W/nf + 0.29)'"
nrd="'0.29 / W'" nrs="'0.29 / W'"
sa=0 sb=0 sd=0
model=nfet_01v8
spiceprefix=X
}
C {sky130_fd_pr/nfet_01v8.sym} 1110 -190 0 0 {name=M7
L=8.0
W=1.0
nf=1
mult=1
ad="'int((nf+1)/2) * W/nf * 0.29'" 
pd="'2*int((nf+1)/2) * (W/nf + 0.29)'"
as="'int((nf+2)/2) * W/nf * 0.29'" 
ps="'2*int((nf+2)/2) * (W/nf + 0.29)'"
nrd="'0.29 / W'" nrs="'0.29 / W'"
sa=0 sb=0 sd=0
model=nfet_01v8
spiceprefix=X
}
C {sky130_fd_pr/nfet_01v8.sym} 1200 -190 0 0 {name=M12
L=8.0
W=1.0
nf=1
mult=1
ad="'int((nf+1)/2) * W/nf * 0.29'" 
pd="'2*int((nf+1)/2) * (W/nf + 0.29)'"
as="'int((nf+2)/2) * W/nf * 0.29'" 
ps="'2*int((nf+2)/2) * (W/nf + 0.29)'"
nrd="'0.29 / W'" nrs="'0.29 / W'"
sa=0 sb=0 sd=0
model=nfet_01v8
spiceprefix=X
}
C {sky130_fd_pr/nfet_01v8.sym} 1270 -190 0 0 {name=M17
L=8.0
W=1.0
nf=1
mult=1
ad="'int((nf+1)/2) * W/nf * 0.29'" 
pd="'2*int((nf+1)/2) * (W/nf + 0.29)'"
as="'int((nf+2)/2) * W/nf * 0.29'" 
ps="'2*int((nf+2)/2) * (W/nf + 0.29)'"
nrd="'0.29 / W'" nrs="'0.29 / W'"
sa=0 sb=0 sd=0
model=nfet_01v8
spiceprefix=X
}
C {sky130_fd_pr/nfet_01v8.sym} 1340 -190 0 0 {name=M18
L=8.0
W=1.0
nf=1
mult=1
ad="'int((nf+1)/2) * W/nf * 0.29'" 
pd="'2*int((nf+1)/2) * (W/nf + 0.29)'"
as="'int((nf+2)/2) * W/nf * 0.29'" 
ps="'2*int((nf+2)/2) * (W/nf + 0.29)'"
nrd="'0.29 / W'" nrs="'0.29 / W'"
sa=0 sb=0 sd=0
model=nfet_01v8
spiceprefix=X
}
C {sky130_fd_pr/nfet_01v8.sym} 310 -200 0 0 {name=M3
L=8.0
W=1.0
nf=1
mult=1
ad="'int((nf+1)/2) * W/nf * 0.29'" 
pd="'2*int((nf+1)/2) * (W/nf + 0.29)'"
as="'int((nf+2)/2) * W/nf * 0.29'" 
ps="'2*int((nf+2)/2) * (W/nf + 0.29)'"
nrd="'0.29 / W'" nrs="'0.29 / W'"
sa=0 sb=0 sd=0
model=nfet_01v8
spiceprefix=X
}
C {sky130_fd_pr/nfet_01v8.sym} 400 -200 0 0 {name=M19
L=8.0
W=1.0
nf=1
mult=1
ad="'int((nf+1)/2) * W/nf * 0.29'" 
pd="'2*int((nf+1)/2) * (W/nf + 0.29)'"
as="'int((nf+2)/2) * W/nf * 0.29'" 
ps="'2*int((nf+2)/2) * (W/nf + 0.29)'"
nrd="'0.29 / W'" nrs="'0.29 / W'"
sa=0 sb=0 sd=0
model=nfet_01v8
spiceprefix=X
}
C {sky130_fd_pr/nfet_01v8.sym} 480 -200 0 0 {name=M20
L=8.0
W=1.0
nf=1
mult=1
ad="'int((nf+1)/2) * W/nf * 0.29'" 
pd="'2*int((nf+1)/2) * (W/nf + 0.29)'"
as="'int((nf+2)/2) * W/nf * 0.29'" 
ps="'2*int((nf+2)/2) * (W/nf + 0.29)'"
nrd="'0.29 / W'" nrs="'0.29 / W'"
sa=0 sb=0 sd=0
model=nfet_01v8
spiceprefix=X
}
C {sky130_fd_pr/nfet_01v8.sym} 560 -200 0 0 {name=M21
L=8.0
W=1.0
nf=1
mult=1
ad="'int((nf+1)/2) * W/nf * 0.29'" 
pd="'2*int((nf+1)/2) * (W/nf + 0.29)'"
as="'int((nf+2)/2) * W/nf * 0.29'" 
ps="'2*int((nf+2)/2) * (W/nf + 0.29)'"
nrd="'0.29 / W'" nrs="'0.29 / W'"
sa=0 sb=0 sd=0
model=nfet_01v8
spiceprefix=X
}
C {sky130_fd_pr/nfet_01v8.sym} 640 -200 0 0 {name=M22
L=8.0
W=1.0
nf=1
mult=1
ad="'int((nf+1)/2) * W/nf * 0.29'" 
pd="'2*int((nf+1)/2) * (W/nf + 0.29)'"
as="'int((nf+2)/2) * W/nf * 0.29'" 
ps="'2*int((nf+2)/2) * (W/nf + 0.29)'"
nrd="'0.29 / W'" nrs="'0.29 / W'"
sa=0 sb=0 sd=0
model=nfet_01v8
spiceprefix=X
}
C {sky130_fd_pr/nfet_01v8.sym} 730 -200 0 0 {name=M23
L=8.0
W=1.0
nf=1
mult=1
ad="'int((nf+1)/2) * W/nf * 0.29'" 
pd="'2*int((nf+1)/2) * (W/nf + 0.29)'"
as="'int((nf+2)/2) * W/nf * 0.29'" 
ps="'2*int((nf+2)/2) * (W/nf + 0.29)'"
nrd="'0.29 / W'" nrs="'0.29 / W'"
sa=0 sb=0 sd=0
model=nfet_01v8
spiceprefix=X
}
C {sky130_fd_pr/nfet_01v8.sym} 810 -200 0 0 {name=M24
L=8.0
W=1.0
nf=1
mult=1
ad="'int((nf+1)/2) * W/nf * 0.29'" 
pd="'2*int((nf+1)/2) * (W/nf + 0.29)'"
as="'int((nf+2)/2) * W/nf * 0.29'" 
ps="'2*int((nf+2)/2) * (W/nf + 0.29)'"
nrd="'0.29 / W'" nrs="'0.29 / W'"
sa=0 sb=0 sd=0
model=nfet_01v8
spiceprefix=X
}
C {sky130_fd_pr/nfet_01v8.sym} 890 -200 0 0 {name=M25
L=8.0
W=1.0
nf=1
mult=1
ad="'int((nf+1)/2) * W/nf * 0.29'" 
pd="'2*int((nf+1)/2) * (W/nf + 0.29)'"
as="'int((nf+2)/2) * W/nf * 0.29'" 
ps="'2*int((nf+2)/2) * (W/nf + 0.29)'"
nrd="'0.29 / W'" nrs="'0.29 / W'"
sa=0 sb=0 sd=0
model=nfet_01v8
spiceprefix=X
}
C {devices/lab_pin.sym} -150 -1480 0 0 {name=p16 sig_type=std_logic lab=weight0}
C {devices/gnd.sym} -150 -1372.5 0 0 {name=l23 lab=GND}
C {devices/gnd.sym} -40 -1272.5 0 0 {name=l24 lab=GND}
C {devices/gnd.sym} 70 -1160 0 0 {name=l25 lab=GND}
C {devices/gnd.sym} 200 -1060 0 0 {name=l28 lab=GND}
C {devices/vsource.sym} -150 -1420 0 0 {name=V22 value=1.8
}
C {devices/vsource.sym} -40 -1320 0 0 {name=V23 value=1.8
}
C {devices/vsource.sym} 70 -1210 0 0 {name=V24 value=1.8
}
C {devices/vsource.sym} 200 -1110 0 0 {name=V29 value=1.8
}
